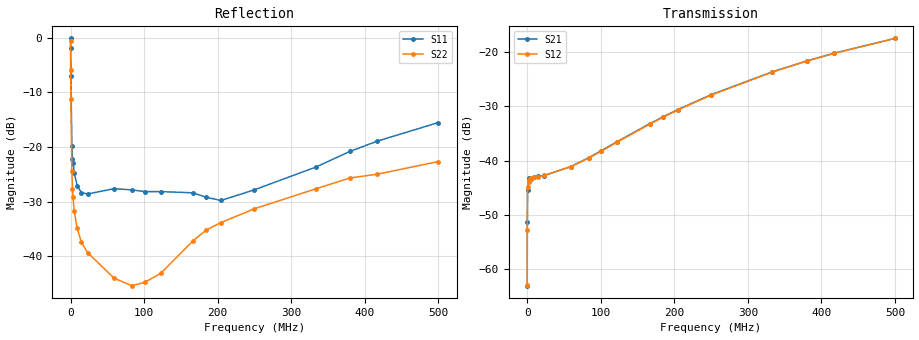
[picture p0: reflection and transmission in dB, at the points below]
#  HZ  S  MA  R  50.00
! Rohde & Schwarz Vector Network Analyzer
! Rohde-Schwarz,ZNL6-2Port,1323001206101378,1.50.1.34-21.10.1.104
! Created: UTC 2/4/2024, 10:00:55 AM
! freq[Hz]  mag:S11  ang:S11  mag:S21  ang:S21  mag:S12  ang:S12  mag:S22  ang:S22
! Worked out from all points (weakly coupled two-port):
!   6000 points, 5 kHz to 500 MHz, reference 50 ohm
!   highest |S21| = -17.50 dB at 500 MHz (marker M1); lowest = -63.0 dB at 5 kHz (marker M2)
!   lowest |S11| = -29.8 dB at 204.5 MHz (marker M3), VSWR 1.07, Z = 49.5 + j3.19 ohm
!   |S11| at or under -10 dB: 637.6 kHz to end of sweep
!   |S22| runs from -45.5 to -0.5 dB; largest |S21 - S12| = 0.003
!   S11 on the Smith chart (normalised r, x): 5 kHz: 0.01, +0.02; 88.35 kHz: 0.15, +0.61; 421.7 kHz: 0.55, +0.59; 1.755 MHz: 0.86, +0.13; 500 MHz: 1.36, -0.16
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5000  0.986 177.5  0.0007064 -17.8  0.0007132 -18.3  0.9421 170.7
88346.39  0.8098 116.2  0.002701 -122.5  0.002275 -120.7  0.5021 102.6
421732  0.449 106.9  0.005395 -158.2  0.005728 -162.1  0.277 79.6
1755274  0.1016 131.3  0.006635 -173.5  0.00664 -173.8  0.0598 116.0
2588738  0.07701 136.0  0.006977 -167.1  0.006331 176.3  0.04149 123.7
3255509  0.0718 137.6  0.006758 -173.9  0.006813 -178.1  0.03478 122.4
5005783  0.05803 139.7  0.006777 -176.2  0.006973 179.9  0.02594 123.8
8923064  0.04437 146.1  0.007012 179.9  0.006996 179.1  0.018 128.1
1.475731e7  0.03821 154.5  0.007154 176.7  0.007058 175.6  0.0134 132.1
2.325864e7  0.03713 162.5  0.007278 173.3  0.007322 173.4  0.01076 137.8
5.934763e7  0.04153 168.2  0.008823 163.0  0.0088 162.4  0.006287 173.6
8.335139e7  0.04049 162.9  0.01062 157.8  0.01051 155.7  0.005376 -140.9
1.006041e8  0.03905 154.9  0.01234 154.1  0.0122 151.6  0.005762 -118.3
1.224408e8  0.03904 143.8  0.01496 149.4  0.01481 147.0  0.006958 -111.1
1.666978e8  0.03806 125.8  0.02188 139.9  0.02167 137.6  0.01388 -113.6
1.844506e8  0.03465 114.8  0.02523 136.1  0.02501 133.9  0.01735 -110.1
2.04537e8  0.03238 97.0  0.02942 131.8  0.02917 129.5  0.02035 -106.5
2.500442e8  0.04056 60.5  0.0404 122.3  0.04006 119.3  0.0272 -111.5
3.333906e8  0.06542 18.5  0.06568 102.5  0.06534 101.4  0.04138 -122.8
3.801479e8  0.09123 4.9  0.08268 93.1  0.0824 91.5  0.05208 -129.1
4.16737e8  0.1129 -3.6  0.09714 84.9  0.09696 84.1  0.0563 -133.4
5e8  0.1672 -19.7  0.1333 65.3  0.1331 65.8  0.07348 -149.0
